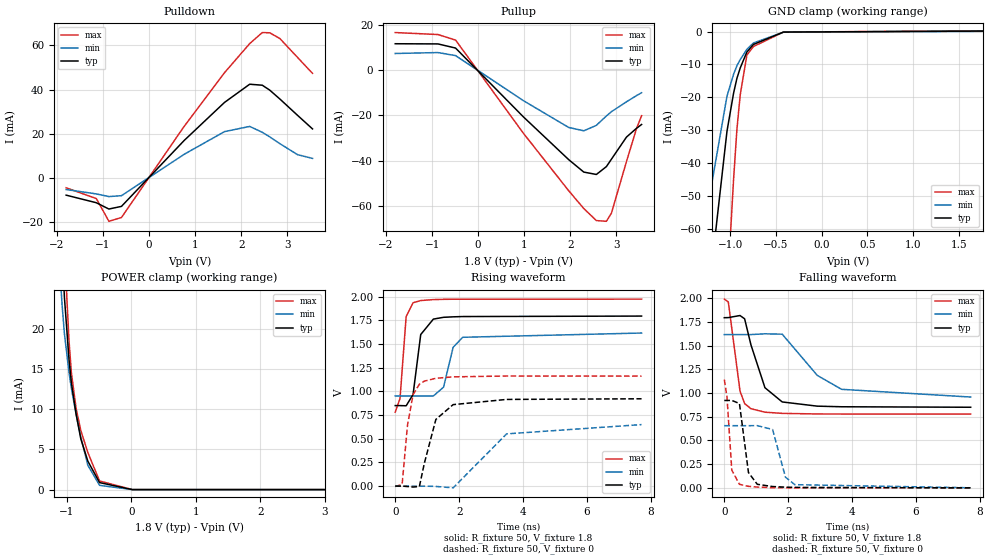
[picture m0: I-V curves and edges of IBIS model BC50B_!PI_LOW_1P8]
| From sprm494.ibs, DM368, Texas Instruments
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|   Model Cell BC50B_!PI_LOW_1P8
|BC1833DV50BTHYPBFZP_!PI_LOW_1P8
[Model]   BC50B_!PI_LOW_1P8
Model_type   I/O
Polarity   Non-Inverting
Enable   Active-Low
Vinl =  0.63V
Vinh =  1.17V
Cref =  15pF
Rref =  100.00M
Vref =  0V
Vmeas =  0.9
C_comp   1.889253p   1.773057p   1.933707p
[Model Spec]
Vinl   0.63V   0.567V   0.693V
Vinh   1.17V   1.053V   1.287V
[Temperature Range]   25   125   -40
[Voltage Range]   1.8   1.62   1.98
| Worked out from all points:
|   slope of the pulldown table from 0 to 0.27 V, typ, clamps not added: 43.6 ohm
|   slope of the pullup table from 0 to 0.27 V, typ, clamps not added: 46.6 ohm
|   GND clamp passes 1 mA (typ) near -0.57 V on its own axis
|   POWER clamp passes 1 mA (typ) near -0.50 V on its own axis
|   rising waveform, R_fixture 50, V_fixture 1.8: 20-80 % time 213ps typ, 291ps min, 147ps max; typ from 0.851 V to 1.8 V
|   rising waveform, R_fixture 50, V_fixture 0: 20-80 % time 446ps typ, 938ps min, 249ps max; typ from 0 V to 0.923 V
|   falling waveform, R_fixture 50, V_fixture 1.8: 20-80 % time 531ps typ, 1.17ns min, 288ps max; typ from 1.8 V to 0.851 V
|   falling waveform, R_fixture 50, V_fixture 0: 20-80 % time 166ps typ, 259ps min, 126ps max; typ from 0.923 V to 0 V
[POWER_clamp]
|   voltage   I(typ)   I(min)   I(max)
-1.8V     212.6mA    175.4mA    247.3mA
-1.145V   43.89mA    32.3mA     55.58mA
-1.073V   29.96mA    23.1mA     37.82mA
-1.036V   23.94mA    19.41mA    29.73mA
-963.6mV  16.07mA    14.51mA    18.39mA
-927.3mV  13.26mA    12.56mA    14.5mA
-854.5mV  9.382mA    9.37mA     10.09mA
-781.8mV  6.319mA    6.538mA    7.348mA
-672.7mV  3.536mA    3.026mA    4.61mA
-490.9mV  870.1uA    529.1uA    1.07mA
18.18mV   0A         0A         0A
3.6V      0A         0A         0A
[Pulldown]
|   voltage   I(typ)   I(min)   I(max)
-1.8V     -7.67mA    -5.126mA   -4.339mA
-1.145V   -11.1mA    -7.106mA   -9.219mA
-872.7mV  -13.94mA   -8.311mA   -19.49mA
-600mV    -12.75mA   -7.913mA   -17.78mA
763.6mV   17.11mA    10.84mA    23.53mA
1.636V    34.26mA    21.05mA    47.69mA
2.182V    42.48mA    23.41mA    60.84mA
2.455V    42.04mA    20.75mA    65.84mA
2.618V    39.8mA     18.68mA    65.73mA
2.836V    35.82mA    15.63mA    63.15mA
3.218V    28.47mA    10.66mA    54.66mA
3.545V    22.28mA    8.953mA    47.39mA
[Pullup]
|   voltage   I(typ)   I(min)   I(max)
-1.8V     11.79mA    7.463mA    16.74mA
-872.7mV  11.71mA    7.882mA    15.87mA
-490.9mV  9.874mA    6.533mA    13.41mA
981.8mV   -20.64mA   -13.44mA   -27.9mA
1.964V    -39.57mA   -25.31mA   -53.36mA
2.291V    -45.08mA   -26.79mA   -61.23mA
2.564V    -46.14mA   -24.37mA   -66.57mA
2.782V    -42.64mA   -20.2mA    -66.89mA
2.891V    -39.36mA   -18.32mA   -63.26mA
3.218V    -29.56mA   -13.93mA   -40.37mA
3.436V    -25.67mA   -11.18mA   -25.75mA
3.545V    -23.99mA   -9.92mA    -20.12mA
[GND_clamp]
|   voltage   I(typ)   I(min)   I(max)
-1.8V     -250.5mA   -178.5mA   -583.4mA
-1.364V   -117.2mA   -78.71mA   -289.4mA
-1.255V   -85.45mA   -55.93mA   -216.8mA
-1.218V   -75.29mA   -48.85mA   -193mA
-1.036V   -30.35mA   -19.65mA   -80.5mA
-963.6mV  -18.72mA   -12.97mA   -44.87mA
-927.3mV  -14.24mA   -10.4mA    -29.75mA
-890.9mV  -11.07mA   -8.514mA   -19.23mA
-818.2mV  -6.213mA   -5.413mA   -7.125mA
-745.5mV  -3.899mA   -3.449mA   -4.536mA
-418.2mV  -148.7uA   -185.6uA   -149.9uA
1.764V    152.1uA    81.85uA    241.4uA
[Ramp]
| variable   typ   min   max
dV/dt_f  0.5845332/0.5363571n  0.4133938/1.205579n   0.7293639/0.2878601n
dV/dt_r   0.566762/0.4447432n  0.4056353/0.9673423n   0.705536/0.2480989n
R_load = 50
[Rising Waveform]
R_fixture = 50
V_fixture = 1.8
V_fixture_min = 1.62
V_fixture_max = 1.98
|   time   V(typ)   V(min)   V(max)
0s        850.6mV    952.7mV    781.8mV
150ps     850.6mV    952.7mV    925.2mV
342ps     848.8mV    952.7mV    1.791V
558ps     966.9mV    952.7mV    1.937V
798ps     1.601V     952.7mV    1.96V
1.194ns   1.764V     952.4mV    1.97V
1.512ns   1.783V     1.045V     1.973V
1.812ns   1.788V     1.466V     1.974V
2.112ns   1.791V     1.572V     1.974V
7.71ns    1.796V     1.617V     1.975V
[Rising Waveform]
R_fixture = 50
V_fixture = 0
V_fixture_min = 0
V_fixture_max = 0
|   time   V(typ)   V(min)   V(max)
0s        10.67uV    14.59uV    -4.323mV
216ps     61.35uV    17.46uV    18.42mV
384ps     -4.078mV   14.88uV    643.3mV
558ps     -9.787mV   7.984uV    965.7mV
756ps     -4.045mV   2.626uV    1.076V
912ps     242.5mV    12.02uV    1.109V
1.272ns   704.6mV    -3.059mV   1.139V
1.812ns   860.8mV    -18.19mV   1.154V
3.486ns   915.8mV    551.9mV    1.163V
7.71ns    922.5mV    650mV      1.162V
[Falling Waveform]
R_fixture = 50
V_fixture = 1.8
V_fixture_min = 1.62
V_fixture_max = 1.98
|   time   V(typ)   V(min)   V(max)
0s        1.796V     1.618V     1.992V
126ps     1.797V     1.618V     1.962V
492ps     1.819V     1.618V     1.021V
636ps     1.784V     1.618V     889.7mV
834ps     1.509V     1.618V     835.4mV
1.272ns   1.057V     1.626V     798.6mV
1.812ns   906.8mV    1.622V     786.2mV
2.91ns    862.4mV    1.187V     779.9mV
3.672ns   856mV      1.04V      779.3mV
7.71ns    850.8mV    958.6mV    779.1mV
[Falling Waveform]
R_fixture = 50
V_fixture = 0
V_fixture_min = 0
V_fixture_max = 0
|   time   V(typ)   V(min)   V(max)
0s        922.7mV    656.5mV    1.143V
84ps      922.5mV    656.5mV    959mV
234ps     923.1mV    656.5mV    187.8mV
474ps     890.1mV    656.5mV    37.52mV
756ps     161.5mV    656.5mV    15.91mV
1.032ns   37.72mV    657mV      8.269mV
1.512ns   13.76mV    616.1mV    2.199mV
1.914ns   7.641mV    112.6mV    712.5uV
2.208ns   4.93mV     33.6mV     318.1uV
7.71ns    26.96uV    956.8uV    4.596uV
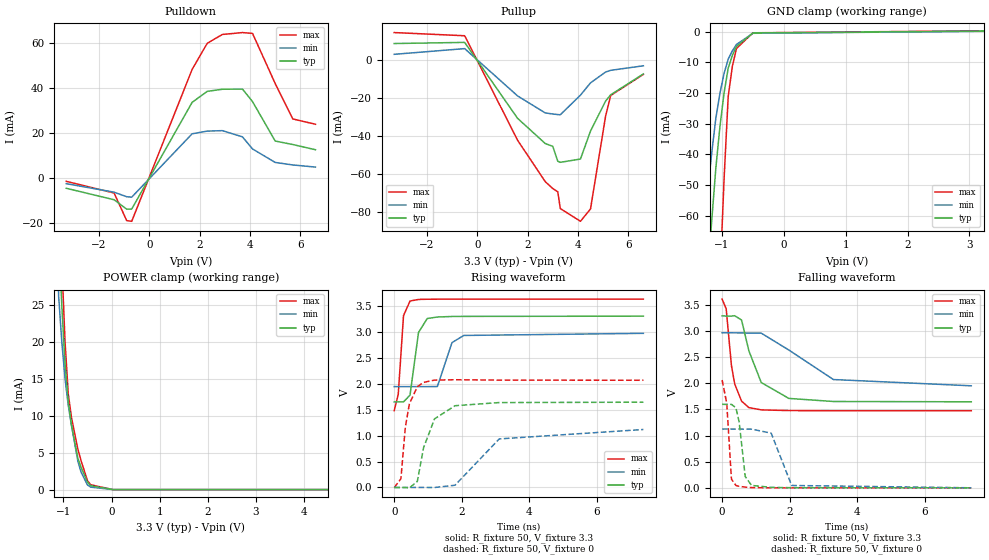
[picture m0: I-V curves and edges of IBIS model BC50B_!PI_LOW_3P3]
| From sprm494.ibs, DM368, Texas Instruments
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|   Model Cell BC50B_!PI_LOW_3P3
|BC1833DV50BTHYPBFZP_!PI_LOW_3P3
[Model]   BC50B_!PI_LOW_3P3
Model_type   I/O
Polarity   Non-Inverting
Enable   Active-Low
Vinl =  0.8V
Vinh =  2V
Cref =  15pF
Rref =  100.00M
Vref =  0V
Vmeas =  1.65
C_comp   1.614302p   1.431606p   1.718607p
[Model Spec]
Vinl   0.8V   0.8V   0.8V
Vinh   2V   2V   2V
[Temperature Range]   25   125   -40
[Voltage Range]   3.3   2.97   3.63
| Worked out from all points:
|   slope of the pulldown table from 0 to 0.495 V, typ, clamps not added: 43.6 ohm
|   slope of the pullup table from 0 to 0.495 V, typ, clamps not added: 49.2 ohm
|   GND clamp passes 1 mA (typ) near -0.55 V on its own axis
|   POWER clamp passes 1 mA (typ) near -0.50 V on its own axis
|   rising waveform, R_fixture 50, V_fixture 3.3: 20-80 % time 192ps typ, 274ps min, 121ps max; typ from 1.65 V to 3.3 V
|   rising waveform, R_fixture 50, V_fixture 0: 20-80 % time 437ps typ, 952ps min, 233ps max; typ from 0 V to 1.64 V
|   falling waveform, R_fixture 50, V_fixture 3.3: 20-80 % time 535ps typ, 946ps min, 246ps max; typ from 3.29 V to 1.65 V
|   falling waveform, R_fixture 50, V_fixture 0: 20-80 % time 155ps typ, 282ps min, 108ps max; typ from 1.6 V to 0 V
[POWER_clamp]
|   voltage   I(typ)   I(min)   I(max)
-3.3V     629.6mA    736.9mA    707.5mA
-1.1V     34.92mA    26.14mA    44.41mA
-1.033V   24.71mA    19.89mA    30.46mA
-966.7mV  17.04mA    14.97mA    19.98mA
-900mV    11.92mA    11.4mA     12.95mA
-833.3mV  8.768mA    8.668mA    9.749mA
-700mV    4.221mA    3.846mA    5.471mA
-633.3mV  3.019mA    2.354mA    3.9mA
-500mV    998.2uA    619.3uA    1.21mA
-433.3mV  528.2uA    335.2uA    654.1uA
33.33mV   0A         0A         0A
6.6V      0A         0A         0A
[Pulldown]
|   voltage   I(typ)   I(min)   I(max)
-3.3V     -4.448mA   -2.4mA     -1.374mA
-1.4V     -9.542mA   -6.187mA   -6.549mA
-900mV    -13.71mA   -8.202mA   -18.8mA
-700mV    -13.65mA   -8.389mA   -19.1mA
1.7V      33.68mA    19.73mA    48.3mA
2.3V      38.57mA    20.92mA    59.89mA
2.9V      39.49mA    21.13mA    63.8mA
3.7V      39.58mA    18.37mA    64.65mA
4.1V      34.01mA    13mA       64.27mA
5V        16.52mA    7.025mA    42.04mA
5.7V      14.97mA    5.897mA    26.31mA
6.6V      12.66mA    4.964mA    23.97mA
[Pullup]
|   voltage   I(typ)   I(min)   I(max)
-3.3V     8.925mA    3.225mA    14.72mA
-500mV    9.531mA    6.242mA    13.04mA
1.6V      -30.57mA   -18.73mA   -42.11mA
2.7V      -43.89mA   -27.73mA   -64.03mA
3V        -45.38mA   -28.31mA   -67.67mA
3.2V      -53.28mA   -28.6mA    -69.43mA
3.3V      -53.83mA   -28.7mA    -78.25mA
4.1V      -52.1mA    -18.35mA   -84.99mA
4.5V      -37.33mA   -11.85mA   -78.48mA
5.1V      -21.45mA   -6.119mA   -29.35mA
5.3V      -18.16mA   -5.226mA   -18.53mA
6.6V      -7.127mA   -2.839mA   -7.361mA
[GND_clamp]
|   voltage   I(typ)   I(min)   I(max)
-3.3V     -715.9mA   -742.1mA   -1.572A
-1.3V     -98.63mA   -65.27mA   -247mA
-1.233V   -79.79mA   -52.01mA   -203.1mA
-1.167V   -61.75mA   -39.66mA   -160.1mA
-1.1V     -44.51mA   -28.24mA   -117.9mA
-1.033V   -30.84mA   -20.05mA   -80.28mA
-966.7mV  -19.98mA   -13.64mA   -48.03mA
-900mV    -11.94mA   -9.003mA   -21.15mA
-833.3mV  -7.788mA   -6.31mA    -11.4mA
-766.7mV  -4.854mA   -4.212mA   -5.541mA
-500mV    -477.2uA   -568.3uA   -409.6uA
3.233V    154.8uA    93.83uA    247.5uA
[Ramp]
| variable   typ   min   max
dV/dt_f  0.9893725/0.5328737n  0.6158454/0.9841454n   1.288227/0.2457634n
dV/dt_r  0.9892293/0.4367277n  0.6801084/0.9817556n   1.249182/0.2364726n
R_load = 50
[Rising Waveform]
R_fixture = 50
V_fixture = 3.3
V_fixture_min = 2.97
V_fixture_max = 3.63
|   time   V(typ)   V(min)   V(max)
0s        1.647V     1.941V     1.477V
120ps     1.647V     1.941V     1.793V
276ps     1.647V     1.941V     3.307V
468ps     1.777V     1.941V     3.587V
720ps     2.983V     1.941V     3.618V
978ps     3.251V     1.941V     3.622V
1.278ns   3.28V      1.943V     3.623V
1.71ns    3.29V      2.787V     3.624V
2.058ns   3.292V     2.925V     3.624V
7.374ns   3.296V     2.966V     3.624V
[Rising Waveform]
R_fixture = 50
V_fixture = 0
V_fixture_min = 0
V_fixture_max = 0
|   time   V(typ)   V(min)   V(max)
0s        4.095uV    9.794uV    -3.527mV
198ps     6.659uV    12.37uV    167.9mV
330ps     -500.4uV   11.43uV    1.162V
450ps     -7.136mV   6.654uV    1.609V
684ps     116.5mV    644.1nV    1.938V
870ps     766.3mV    789.4nV    2.022V
1.194ns   1.321V     -385.8uV   2.066V
1.8ns     1.573V     43.53mV    2.073V
3.108ns   1.634V     934.5mV    2.066V
7.374ns   1.641V     1.116V     2.063V
[Falling Waveform]
R_fixture = 50
V_fixture = 3.3
V_fixture_min = 2.97
V_fixture_max = 3.63
|   time   V(typ)   V(min)   V(max)
0s        3.291V     2.968V     3.612V
120ps     3.288V     2.968V     3.429V
276ps     3.287V     2.968V     2.34V
372ps     3.295V     2.967V     1.99V
576ps     3.211V     2.965V     1.659V
792ps     2.622V     2.962V     1.537V
1.158ns   2.016V     2.961V     1.492V
1.974ns   1.712V     2.638V     1.479V
3.294ns   1.653V     2.073V     1.477V
7.374ns   1.647V     1.953V     1.477V
[Falling Waveform]
R_fixture = 50
V_fixture = 0
V_fixture_min = 0
V_fixture_max = 0
|   time   V(typ)   V(min)   V(max)
0s        1.599V     1.126V     2.064V
138ps     1.597V     1.126V     1.615V
276ps     1.598V     1.126V     168.2mV
408ps     1.534V     1.125V     45.07mV
504ps     1.26V      1.125V     29.16mV
684ps     216.2mV    1.124V     13.89mV
870ps     46.97mV    1.124V     5.217mV
1.452ns   9.609mV    1.047V     301.4uV
2.058ns   2.815mV    45.73mV    23.18uV
7.374ns   11.2uV     1.054mV    302.1nV
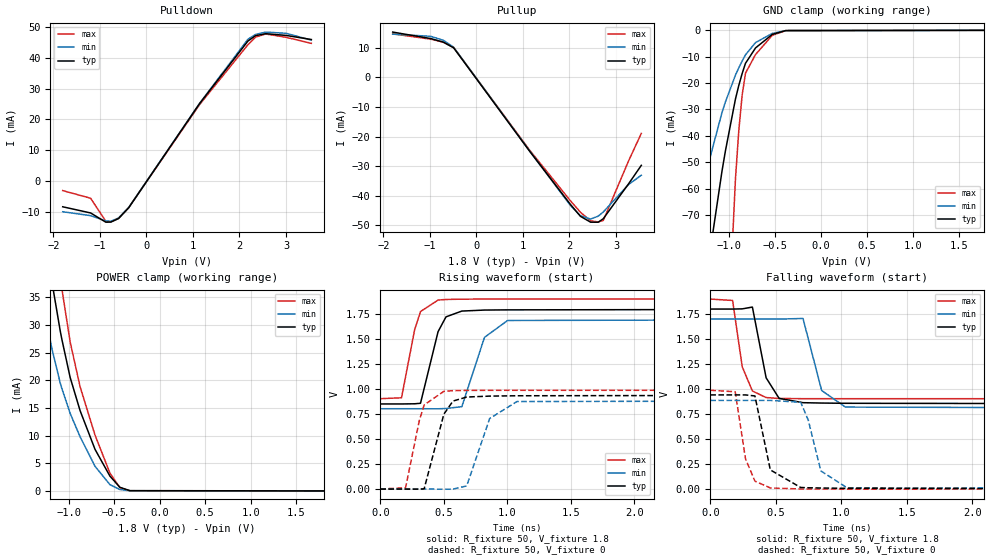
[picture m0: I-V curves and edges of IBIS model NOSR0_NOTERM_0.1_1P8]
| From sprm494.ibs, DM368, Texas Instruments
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|   Model Cell NOSR0_NOTERM_0.1_1P8
|NOSR0_NOTERM_0.1_1P8
[Model]   NOSR0_NOTERM_0.1_1P8
Model_type   I/O
Polarity   Non-Inverting
Enable   Active-Low
Vinl = 0.8V
Vinh = 2V
Cref =  15.0000pF
Rref =  100.0000M
Vref =  0V
Vmeas =  0.9
C_comp   3.009089p   2.23501p   3.95018p
[Model Spec]
Vinl   0.8V   0.8V   0.8V
Vinh   2V   2V   2V
[Temperature Range]   25   125   -40
[Voltage Range]   1.8   1.7   1.9
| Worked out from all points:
|   slope of the pulldown table from 0 to 0.27 V, typ, clamps not added: 44.1 ohm
|   slope of the pullup table from 0 to 0.27 V, typ, clamps not added: 45.3 ohm
|   GND clamp passes 1 mA (typ) near -0.50 V on its own axis
|   POWER clamp passes 1 mA (typ) near -0.46 V on its own axis
|   rising waveform, R_fixture 50, V_fixture 1.8: 20-80 % time 110ps typ, 134ps min, 95.7ps max; typ from 0.851 V to 1.8 V
|   rising waveform, R_fixture 50, V_fixture 0: 20-80 % time 113ps typ, 139ps min, 99.3ps max; typ from 0 V to 0.942 V
|   falling waveform, R_fixture 50, V_fixture 1.8: 20-80 % time 83.4ps typ, 98.5ps min, 76.6ps max; typ from 1.8 V to 0.851 V
|   falling waveform, R_fixture 50, V_fixture 0: 20-80 % time 81.1ps typ, 105ps min, 73.3ps max; typ from 0.942 V to 0 V
[POWER_clamp]
|   voltage   I(typ)   I(min)   I(max)
-1.8V     107.1mA    82.35mA    134.1mA
-1.327V   53.28mA    37.61mA    69.48mA
-1.182V   37.78mA    25.71mA    50.1mA
-1.091V   28.94mA    19.51mA    38.64mA
-1.073V   27.41mA    18.51mA    36.54mA
-981.8mV  20.5mA     14.01mA    26.92mA
-872.7mV  14.5mA     9.783mA    18.82mA
-709.1mV  7.513mA    4.449mA    10.09mA
-545.5mV  2.674mA    1.139mA    3.211mA
-436.4mV  654.9uA    255.5uA    594.1uA
-327.3mV  54.9uA     31.45uA    28.9uA
1.8V      5.504nA    121.3nA    1.604nA
[Pulldown]
|   voltage   I(typ)   I(min)   I(max)
-1.8V     -8.351mA   -9.956mA   -3.097mA
-1.2V     -10.35mA   -11.23mA   -5.575mA
-872.7mV  -13.35mA   -12.93mA   -13.07mA
-763.6mV  -13.31mA   -13.05mA   -13.22mA
-600mV    -12.16mA   -11.98mA   -12.14mA
-381.8mV  -8.669mA   -8.593mA   -8.643mA
1.145V    25.19mA    25.27mA    24.87mA
2.182V    45.44mA    46.03mA    44.25mA
2.345V    47.19mA    47.58mA    46.72mA
2.564V    47.83mA    48.35mA    47.74mA
3V        47.27mA    47.96mA    46.66mA
3.545V    45.94mA    45.74mA    44.7mA
[Pullup]
|   voltage   I(typ)   I(min)   I(max)
-1.8V     15.34mA    14.64mA    14.75mA
-981.8mV  13.15mA    13.91mA    12.94mA
-709.1mV  11.92mA    12.55mA    11.92mA
-490.9mV  10.05mA    10.24mA    10.12mA
1.145V    -24.96mA   -24.87mA   -24.59mA
2.018V    -42.87mA   -43.22mA   -41.64mA
2.236V    -46.95mA   -46.75mA   -45.58mA
2.455V    -48.93mA   -47.86mA   -48.45mA
2.618V    -48.93mA   -46.89mA   -48.85mA
2.727V    -47.76mA   -45.48mA   -48.34mA
3.273V    -35.91mA   -36.16mA   -28.15mA
3.545V    -29.71mA   -33.05mA   -18.91mA
[GND_clamp]
|   voltage   I(typ)   I(min)   I(max)
-1.8V     -229.3mA   -132mA     -818.5mA
-1.436V   -139.1mA   -79.12mA   -490.7mA
-1.073V   -53.39mA   -31.17mA   -167.2mA
-1.036V   -45.75mA   -27.16mA   -136.8mA
-927.3mV  -26.08mA   -17mA      -56.49mA
-890.9mV  -20.9mA    -14.21mA   -38.02mA
-854.5mV  -16.38mA   -11.64mA   -24.6mA
-818.2mV  -12.5mA    -9.275mA   -16.24mA
-709.1mV  -6.663mA   -4.641mA   -9.157mA
-527.3mV  -1.534mA   -1.158mA   -1.867mA
-381.8mV  -101.4uA   -119.7uA   -85.8uA
1.764V    4.755nA    203.2nA    1.222nA
[Ramp]
| variable   typ   min   max
dV/dt_f  0.5840345/83.79068p   0.5572725/99.27829p   0.6099212/76.90753p
dV/dt_r  0.5671716/0.1130405n  0.5337733/0.1375247n  0.5950157/99.4285p
R_load = 50
[Rising Waveform]
R_fixture = 50
V_fixture = 1.8
V_fixture_min = 1.7
V_fixture_max = 1.9
|   time   V(typ)   V(min)   V(max)
0s        851mV      803.4mV    903.9mV
167.2ps   851mV      803.4mV    912.7mV
270.4ps   852.8mV    803.4mV    1.592V
316.8ps   858mV      803.4mV    1.775V
455.2ps   1.574V     802.9mV    1.89V
517.6ps   1.722V     805.7mV    1.896V
642.4ps   1.78V      824.1mV    1.899V
820.8ps   1.79V      1.517V     1.9V
1.003ns   1.792V     1.686V     1.9V
5.21ns    1.8V       1.698V     1.9V
[Rising Waveform]
R_fixture = 50
V_fixture = 0
V_fixture_min = 0
V_fixture_max = 0
|   time   V(typ)   V(min)   V(max)
0s        84.48nV    277.7nV    33.22nV
199.2ps   48.86nV    347.5nV    13.56mV
307.2ps   -836.1uV   -523.8nV   683.5mV
345.6ps   2.676mV    1.624uV    841mV
500.8ps   749.2mV    -945.5uV   977.5mV
572.8ps   880.2mV    -433.9uV   984mV
680.8ps   920.3mV    31.71mV    986.5mV
861.6ps   929.6mV    705.8mV    987.4mV
1.077ns   933mV      875.4mV    987.8mV
6.031ns   942mV      885.5mV    988.3mV
[Falling Waveform]
R_fixture = 50
V_fixture = 1.8
V_fixture_min = 1.7
V_fixture_max = 1.9
|   time   V(typ)   V(min)   V(max)
0s        1.8V       1.7V       1.9V
170.4ps   1.8V       1.7V       1.886V
244ps     1.802V     1.7V       1.223V
321.6ps   1.82V      1.7V       981.1mV
426.4ps   1.113V     1.7V       915.6mV
525.6ps   907.4mV    1.7V       906.3mV
708ps     864.4mV    1.706V     904.5mV
850.4ps   860.7mV    986.1mV    904.3mV
1.032ns   858.3mV    820.3mV    904.2mV
5.22ns    851mV      805.1mV    903.9mV
[Falling Waveform]
R_fixture = 50
V_fixture = 0
V_fixture_min = 0
V_fixture_max = 0
|   time   V(typ)   V(min)   V(max)
0s        942mV      887.2mV    988.3mV
190.4ps   942mV      887.2mV    973.6mV
268.8ps   941.9mV    887.2mV    304.4mV
340.8ps   931.7mV    887.2mV    80.66mV
458.4ps   192.6mV    887.2mV    12.11mV
690.4ps   16.74mV    868.5mV    1.816mV
748ps     13.99mV    691mV      1.421mV
844.8ps   11.51mV    181.8mV    969.4uV
1.044ns   8.467mV    13.93mV    440.1uV
5.629ns   84.48uV    1.701mV    30.97nV
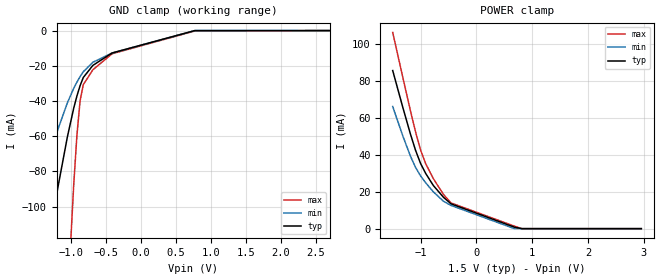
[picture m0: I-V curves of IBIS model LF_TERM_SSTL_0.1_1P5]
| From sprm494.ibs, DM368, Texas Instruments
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|   Model Cell LF_TERM_SSTL_0.1_1P5
|HALF_TERM_SSTL_0.1_1P5
[Model]   LF_TERM_SSTL_0.1_1P5
Model_type   Input
Polarity   Non-Inverting
Vinl =  0.65
Vinh =  0.85
C_comp   3.047242p   2.257596p   4.009695p
[Model Spec]
Vinl   0.65   0.6   0.7
Vinh   0.85   0.8   0.9
[Temperature Range]   25   125   -40
[Voltage Range]   1.5   1.4   1.6
[POWER_clamp]
|   voltage   I(typ)   I(min)   I(max)
-1.5V     85.79mA    66.29mA    106.5mA
-1.318V   65.71mA    50.22mA    81.96mA
-1.182V   51.29mA    39.32mA    63.94mA
-1.091V   42.54mA    33.26mA    52.57mA
-1V       35.33mA    28.59mA    42.61mA
-909.1mV  29.98mA    24.89mA    35.26mA
-772.7mV  23.44mA    20mA       27.19mA
-590.9mV  17.05mA    14.89mA    18.6mA
-454.5mV  13.46mA    12.6mA     13.97mA
681.8mV   796uA      0A         1.352mA
818.2mV   0A         0A         0A
2.955V    0A         0A         0A
[GND_clamp]
|   voltage   I(typ)   I(min)   I(max)
-1.5V     -164.2mA   -98.42mA   -553.9mA
-1.455V   -153.3mA   -92.11mA   -513.2mA
-1.182V   -89.43mA   -56.35mA   -270.9mA
-1.045V   -60.37mA   -41.03mA   -155.7mA
-954.5mV  -44.04mA   -32.8mA    -87.38mA
-909.1mV  -37.15mA   -29.28mA   -59.45mA
-863.6mV  -31.25mA   -26.13mA   -39.8mA
-818.2mV  -26.67mA   -23.37mA   -30.74mA
-681.8mV  -19.78mA   -18.01mA   -22.29mA
-409.1mV  -12.75mA   -12.78mA   -13.2mA
772.7mV   0A         0A         -234.8uA
2.955V    0A         0A         0A
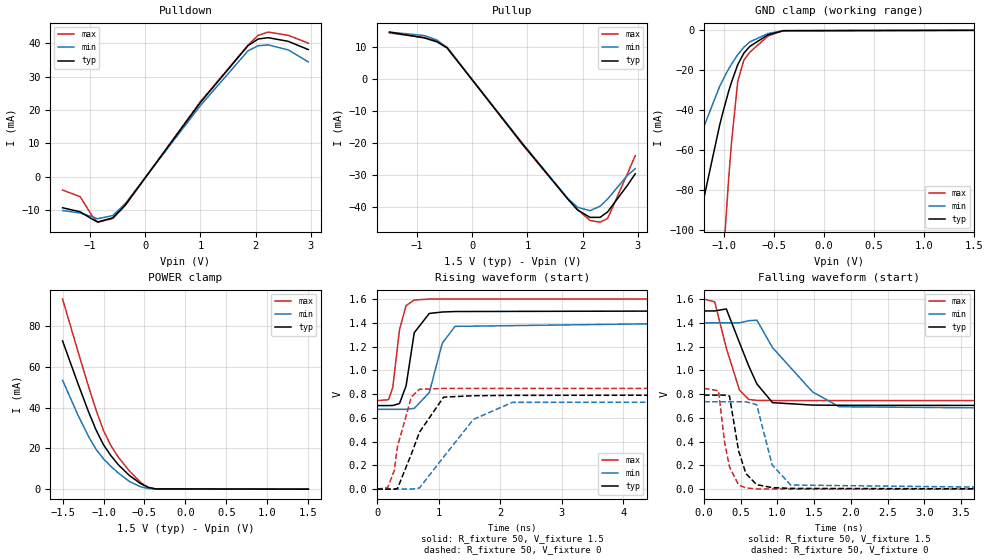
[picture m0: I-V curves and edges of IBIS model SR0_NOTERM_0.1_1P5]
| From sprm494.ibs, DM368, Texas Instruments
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|   Model Cell SR0_NOTERM_0.1_1P5
|SR0_NOTERM_0.1_1P5
[Model]   SR0_NOTERM_0.1_1P5
Model_type   I/O
Polarity   Non-Inverting
Enable   Active-Low
Vinl = 0.8V
Vinh = 2V
Cref =  15.0000pF
Rref =  100.0000M
Vref =  0V
Vmeas =  0.75
C_comp   3.047242p   2.257596p   4.009695p
[Model Spec]
Vinl   0.8V   0.8V   0.8V
Vinh   2V   2V   2V
[Temperature Range]   25   125   -40
[Voltage Range]   1.5   1.4   1.6
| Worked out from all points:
|   slope of the pulldown table from 0 to 0.225 V, typ, clamps not added: 43.5 ohm
|   slope of the pullup table from 0 to 0.225 V, typ, clamps not added: 44.5 ohm
|   GND clamp passes 1 mA (typ) near -0.50 V on its own axis
|   POWER clamp passes 1 mA (typ) near -0.46 V on its own axis
|   rising waveform, R_fixture 50, V_fixture 1.5: 20-80 % time 149ps typ, 230ps min, 113ps max; typ from 0.703 V to 1.5 V
|   rising waveform, R_fixture 50, V_fixture 0: 20-80 % time 342ps typ, 693ps min, 213ps max; typ from 0 V to 0.792 V
|   falling waveform, R_fixture 50, V_fixture 1.5: 20-80 % time 348ps typ, 618ps min, 228ps max; typ from 1.5 V to 0.703 V
|   falling waveform, R_fixture 50, V_fixture 0: 20-80 % time 156ps typ, 196ps min, 125ps max; typ from 0.792 V to 0 V
[POWER_clamp]
|   voltage   I(typ)   I(min)   I(max)
-1.5V     72.7mA     53.42mA    93.21mA
-1.318V   52.38mA    36.87mA    68.38mA
-1.182V   37.83mA    25.73mA    50.19mA
-1.091V   29.01mA    19.56mA    38.73mA
-1V       21.75mA    14.83mA    28.69mA
-909.1mV  16.39mA    11.14mA    21.29mA
-818.2mV  11.93mA    7.898mA    15.6mA
-681.8mV  6.623mA    3.712mA    8.836mA
-545.5mV  2.678mA    1.14mA     3.213mA
-454.5mV  887.8uA    343.9uA    858.4uA
-363.6mV  140.3uA    66.34uA    91.92uA
1.5V      4.339nA    110.3nA    858.8pA
[Pulldown]
|   voltage   I(typ)   I(min)   I(max)
-1.5V     -9.235mA   -10.05mA   -3.95mA
-1.182V   -10.44mA   -10.8mA    -5.906mA
-954.5mV  -12.72mA   -11.97mA   -11.94mA
-863.6mV  -13.5mA    -12.52mA   -13.55mA
-590.9mV  -12.24mA   -11.57mA   -12.48mA
-363.6mV  -8.405mA   -8.003mA   -8.542mA
1V        22.28mA    21.36mA    22.53mA
1.864V    39.29mA    37.74mA    39.44mA
2.045V    41.23mA    39.22mA    42.33mA
2.227V    41.63mA    39.48mA    43.3mA
2.591V    40.53mA    37.98mA    42.34mA
2.955V    38.06mA    34.38mA    39.99mA
[Pullup]
|   voltage   I(typ)   I(min)   I(max)
-1.5V     14.7mA     14.69mA    14.42mA
-863.6mV  12.86mA    13.61mA    13.02mA
-636.4mV  11.64mA    12.19mA    11.92mA
-454.5mV  9.734mA    9.834mA    9.982mA
909.1mV   -20.18mA   -19.98mA   -20.36mA
1.727V    -37.31mA   -37.08mA   -37.22mA
1.909V    -40.82mA   -39.99mA   -40.7mA
2.136V    -43.15mA   -41.06mA   -44.11mA
2.318V    -43.15mA   -39.66mA   -44.65mA
2.455V    -41.43mA   -37.41mA   -43.5mA
2.818V    -33.04mA   -29.95mA   -29.35mA
2.955V    -29.56mA   -27.97mA   -23.91mA
[GND_clamp]
|   voltage   I(typ)   I(min)   I(max)
-1.5V     -154.8mA   -88.21mA   -548.3mA
-1.379V   -125mA     -70.97mA   -438.6mA
-1.045V   -47.59mA   -28.12mA   -144.3mA
-1.015V   -41.63mA   -25.04mA   -120mA
-954.5mV  -30.51mA   -19.31mA   -74.41mA
-924.2mV  -25.71mA   -16.8mA    -55.35mA
-863.6mV  -17.19mA   -12.18mA   -25.62mA
-803mV    -11.46mA   -8.492mA   -15mA
-742.4mV  -8.023mA   -5.771mA   -10.89mA
-560.6mV  -2.222mA   -1.607mA   -2.833mA
-409.1mV  -188.4uA   -199.8uA   -167.8uA
1.5V      4.339nA    282.3nA    668.4pA
[Ramp]
| variable   typ   min   max
dV/dt_f   0.494457/0.3522576n  0.4578104/0.6300302n  0.5257976/0.2342603n
dV/dt_r  0.4755293/0.3418196n   0.441483/0.6948338n  0.5094049/0.2112825n
R_load = 50
[Rising Waveform]
R_fixture = 50
V_fixture = 1.5
V_fixture_min = 1.4
V_fixture_max = 1.6
|   time   V(typ)   V(min)   V(max)
0s        703.4mV    671.8mV    745.7mV
184ps     703.4mV    671.8mV    752.6mV
253.6ps   704.1mV    671.8mV    854.6mV
363.2ps   720.6mV    671.8mV    1.343V
470.4ps   869.9mV    672mV      1.545V
603.2ps   1.317V     680mV      1.592V
847.2ps   1.479V     812.6mV    1.6V
1.058ns   1.491V     1.228V     1.6V
1.265ns   1.495V     1.37V      1.6V
5.491ns   1.5V       1.399V     1.6V
[Rising Waveform]
R_fixture = 50
V_fixture = 0
V_fixture_min = 0
V_fixture_max = 0
|   time   V(typ)   V(min)   V(max)
0s        69.34nV    279.2nV    22nV
170.4ps   3.828uV    332.1nV    12.56mV
276.8ps   -202.3uV   -416nV     154.2mV
330.4ps   5.832mV    6.583uV    358.8mV
556.8ps   296.6mV    234.8uV    776.8mV
688ps     479.6mV    10.11mV    840.9mV
1.08ns    774.4mV    270.5mV    847.6mV
1.565ns   786.4mV    587.2mV    847.9mV
2.197ns   789.4mV    730.2mV    848mV
6.62ns    791.6mV    734mV      848.1mV
[Falling Waveform]
R_fixture = 50
V_fixture = 1.5
V_fixture_min = 1.4
V_fixture_max = 1.6
|   time   V(typ)   V(min)   V(max)
0s        1.5V       1.4V       1.6V
145.6ps   1.5V       1.4V       1.576V
303.2ps   1.517V     1.4V       1.187V
483.2ps   1.232V     1.4V       833.2mV
609.6ps   1.035V     1.418V     754.7mV
720ps     885mV      1.422V     747.2mV
932.8ps   728mV      1.191V     746.1mV
1.477ns   707.7mV    818.5mV    745.9mV
1.84ns    706mV      693.7mV    745.9mV
5.839ns   703.5mV    673.2mV    745.7mV
[Falling Waveform]
R_fixture = 50
V_fixture = 0
V_fixture_min = 0
V_fixture_max = 0
|   time   V(typ)   V(min)   V(max)
0s        791.6mV    735.4mV    848.1mV
197.6ps   791.6mV    735.4mV    828.2mV
278.4ps   791.6mV    735.4mV    402.7mV
346.4ps   783.5mV    735.4mV    187.7mV
470.4ps   322.7mV    735.4mV    35.19mV
569.6ps   131.8mV    735.4mV    10.22mV
716.8ps   37.75mV    711.4mV    2.163mV
926.4ps   13.23mV    205.2mV    826.3uV
1.18ns    6.554mV    34.61mV    340.4uV
6.042ns   51.14uV    1.401mV    23.25nV
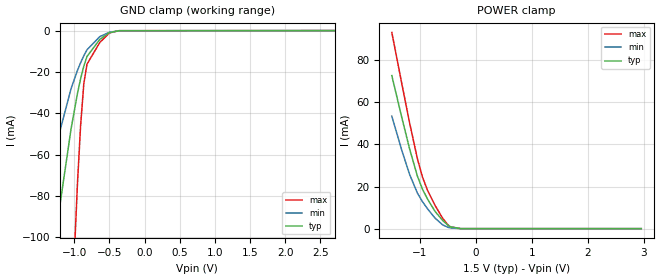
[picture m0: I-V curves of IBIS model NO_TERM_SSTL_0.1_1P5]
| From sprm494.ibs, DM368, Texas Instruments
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|   Model Cell NO_TERM_SSTL_0.1_1P5
|NO_TERM_SSTL_0.1_1P5
[Model]   NO_TERM_SSTL_0.1_1P5
Model_type   Input
Polarity   Non-Inverting
Vinl =  0.65
Vinh =  0.85
C_comp   3.047242p   2.257596p   4.009695p
[Model Spec]
Vinl   0.65   0.6   0.7
Vinh   0.85   0.8   0.9
[Temperature Range]   25   125   -40
[Voltage Range]   1.5   1.4   1.6
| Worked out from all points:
|   GND clamp passes 1 mA (typ) near -0.50 V on its own axis
|   POWER clamp passes 1 mA (typ) near -0.46 V on its own axis
[POWER_clamp]
|   voltage   I(typ)   I(min)   I(max)
-1.5V     72.7mA     53.42mA    93.21mA
-1.318V   52.38mA    36.87mA    68.38mA
-1.182V   37.83mA    25.73mA    50.19mA
-1.045V   25.12mA    17.02mA    33.45mA
-954.5mV  18.89mA    12.91mA    24.66mA
-863.6mV  14.09mA    9.481mA    18.29mA
-727.3mV  8.167mA    4.987mA    10.99mA
-590.9mV  3.871mA    1.783mA    4.897mA
-500mV    1.664mA    664.3uA    1.833mA
-454.5mV  887.8uA    343.9uA    858.4uA
-272.7mV  11.39uA    9.667uA    3.868uA
2.955V    0A         0A         0A
[GND_clamp]
|   voltage   I(typ)   I(min)   I(max)
-1.5V     -154.8mA   -88.21mA   -548.3mA
-1.455V   -143.6mA   -81.7mA    -507.2mA
-1.409V   -132.4mA   -75.24mA   -466mA
-1.045V   -47.59mA   -28.12mA   -144.3mA
-954.5mV  -30.51mA   -19.31mA   -74.41mA
-909.1mV  -23.31mA   -15.54mA   -45.82mA
-863.6mV  -17.19mA   -12.18mA   -25.62mA
-818.2mV  -12.49mA   -9.273mA   -16.23mA
-636.4mV  -4.251mA   -2.918mA   -5.754mA
-500mV    -1.018mA   -818.1uA   -1.152mA
-363.6mV  -64.96uA   -83.03uA   -53.39uA
2.955V    0A         0A         0A
